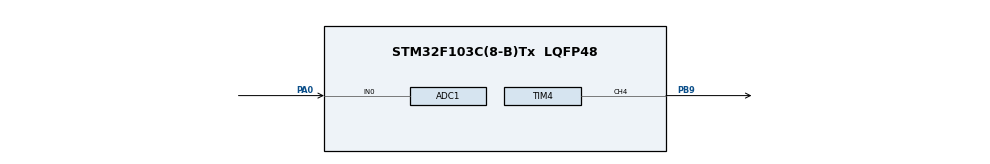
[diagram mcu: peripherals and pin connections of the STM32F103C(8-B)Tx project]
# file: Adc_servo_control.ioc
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ADC1.Channel-0\#ChannelRegularConversion=ADC_CHANNEL_0
ADC1.NbrOfConversionFlag=1
ADC1.Rank-0\#ChannelRegularConversion=1
ADC1.SamplingTime-0\#ChannelRegularConversion=ADC_SAMPLETIME_1CYCLE_5
ADC1.master=1
Dma.ADC1.0.Direction=DMA_PERIPH_TO_MEMORY
Dma.ADC1.0.Instance=DMA1_Channel1
Dma.ADC1.0.MemDataAlignment=DMA_MDATAALIGN_HALFWORD
Dma.ADC1.0.MemInc=DMA_MINC_ENABLE
Dma.ADC1.0.Mode=DMA_CIRCULAR
Dma.ADC1.0.PeriphDataAlignment=DMA_PDATAALIGN_HALFWORD
Dma.ADC1.0.PeriphInc=DMA_PINC_DISABLE
Dma.ADC1.0.Priority=DMA_PRIORITY_HIGH
Dma.Request0=ADC1
Mcu.Family=STM32F1
Mcu.Name=STM32F103C(8-B)Tx
Mcu.Package=LQFP48
NVIC.ADC1_2_IRQn=true\:0\:0\:false\:false\:true\:true\:true\:true
NVIC.DMA1_Channel1_IRQn=true\:0\:0\:false\:false\:true\:false\:true\:true
NVIC.PriorityGroup=NVIC_PRIORITYGROUP_4
NVIC.TIM4_IRQn=true\:0\:0\:false\:false\:true\:true\:true\:true
PA0-WKUP.Signal=ADCx_IN0
PB9.Signal=S_TIM4_CH4
PD0-OSC_IN.Mode=HSE-External-Oscillator
PD0-OSC_IN.Signal=RCC_OSC_IN
PD1-OSC_OUT.Mode=HSE-External-Oscillator
PD1-OSC_OUT.Signal=RCC_OSC_OUT
ProjectManager.HeapSize=0x200
ProjectManager.StackSize=0x400
ProjectManager.TargetToolchain=STM32CubeIDE
RCC.APB1Freq_Value=8000000
RCC.APB2Freq_Value=8000000
SH.ADCx_IN0.0=ADC1_IN0,IN0
SH.S_TIM4_CH4.0=TIM4_CH4,PWM Generation4 CH4
TIM4.Channel-PWM\ Generation4\ CH4=TIM_CHANNEL_4
TIM4.Period=19999
TIM4.Prescaler=71
VP_SYS_VS_ND.Mode=No_Debug
VP_TIM4_VS_ClockSourceINT.Mode=Internal
board=custom

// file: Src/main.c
/* USER CODE END Header */

#include "main.h"

ADC_HandleTypeDef hadc1;
DMA_HandleTypeDef hdma_adc1;
TIM_HandleTypeDef htim4;

/* USER CODE BEGIN PV */
volatile uint16_t pot_v = 0;
/* USER CODE END PV */

void SystemClock_Config(void);
static void MX_GPIO_Init(void);
static void MX_DMA_Init(void);
static void MX_ADC1_Init(void);
static void MX_TIM4_Init(void);

int main(void)
{
    HAL_Init();
    SystemClock_Config();

    MX_GPIO_Init();
    MX_DMA_Init();
    MX_ADC1_Init();
    MX_TIM4_Init();

    /* USER CODE BEGIN 2 */
    HAL_ADCEx_Calibration_Start(&hadc1);
    HAL_ADC_Start_DMA(&hadc1, (uint32_t*)&pot_v, 1);
    HAL_TIM_PWM_Start(&htim4, TIM_CHANNEL_4);
    /* USER CODE END 2 */

    while (1)
    {
        /* USER CODE BEGIN 3 */

        uint32_t pulse = 500 + ((uint32_t)pot_v * 2000 / 4095);
        __HAL_TIM_SET_COMPARE(&htim4, TIM_CHANNEL_4, pulse);

    }
}

/**
  * @retval None
  */
void SystemClock_Config(void)
{
    RCC_OscInitTypeDef RCC_OscInitStruct = {0};
    RCC_ClkInitTypeDef RCC_ClkInitStruct = {0};
    RCC_PeriphCLKInitTypeDef PeriphClkInit = {0};

    RCC_OscInitStruct.OscillatorType = RCC_OSCILLATORTYPE_HSE;
    RCC_OscInitStruct.HSEState = RCC_HSE_ON;
    RCC_OscInitStruct.HSEPredivValue = RCC_HSE_PREDIV_DIV1;
    RCC_OscInitStruct.HSIState = RCC_HSI_ON;
    RCC_OscInitStruct.PLL.PLLState = RCC_PLL_ON;
    RCC_OscInitStruct.PLL.PLLSource = RCC_PLLSOURCE_HSE;
    RCC_OscInitStruct.PLL.PLLMUL = RCC_PLL_MUL9;       // 8MHz x9 = 72MHz
    if (HAL_RCC_OscConfig(&RCC_OscInitStruct) != HAL_OK)
    {
        Error_Handler();
    }

    RCC_ClkInitStruct.ClockType = RCC_CLOCKTYPE_HCLK | RCC_CLOCKTYPE_SYSCLK
                                | RCC_CLOCKTYPE_PCLK1 | RCC_CLOCKTYPE_PCLK2;
    RCC_ClkInitStruct.SYSCLKSource = RCC_SYSCLKSOURCE_PLLCLK;
    RCC_ClkInitStruct.AHBCLKDivider = RCC_SYSCLK_DIV1;
    RCC_ClkInitStruct.APB1CLKDivider = RCC_HCLK_DIV2;
    RCC_ClkInitStruct.APB2CLKDivider = RCC_HCLK_DIV1;
    if (HAL_RCC_ClockConfig(&RCC_ClkInitStruct, FLASH_LATENCY_2) != HAL_OK)
    {
        Error_Handler();
    }

    PeriphClkInit.PeriphClockSelection = RCC_PERIPHCLK_ADC;
    PeriphClkInit.AdcClockSelection = RCC_ADCPCLK2_DIV6;
    if (HAL_RCCEx_PeriphCLKConfig(&PeriphClkInit) != HAL_OK)
    {
        Error_Handler();
    }

}

/**
  * @brief ADC1 Initialization
  * @retval None
  */
static void MX_ADC1_Init(void)
{
    ADC_ChannelConfTypeDef sConfig = {0};

    hadc1.Instance = ADC1;
    hadc1.Init.ScanConvMode = ADC_SCAN_DISABLE;
    hadc1.Init.ContinuousConvMode = ENABLE;
    hadc1.Init.DiscontinuousConvMode = DISABLE;
    hadc1.Init.ExternalTrigConv = ADC_SOFTWARE_START;
    hadc1.Init.DataAlign = ADC_DATAALIGN_RIGHT;
    hadc1.Init.NbrOfConversion = 1;
    if (HAL_ADC_Init(&hadc1) != HAL_OK)
    {
        Error_Handler();
    }

    sConfig.Channel = ADC_CHANNEL_0;
    sConfig.Rank = ADC_REGULAR_RANK_1;
    sConfig.SamplingTime = ADC_SAMPLETIME_55CYCLES_5;
    if (HAL_ADC_ConfigChannel(&hadc1, &sConfig) != HAL_OK)
    {
        Error_Handler();
    }
}

/**
  * @brief TIM4 PWM Initialization

  * @retval None
  */
static void MX_TIM4_Init(void)
{
    TIM_ClockConfigTypeDef sClockSourceConfig = {0};
    TIM_MasterConfigTypeDef sMasterConfig = {0};
    TIM_OC_InitTypeDef sConfigOC = {0};

    htim4.Instance = TIM4;
    htim4.Init.Prescaler = 71;
    htim4.Init.CounterMode = TIM_COUNTERMODE_UP;
    htim4.Init.Period = 19999;
    htim4.Init.ClockDivision = TIM_CLOCKDIVISION_DIV1;
    htim4.Init.AutoReloadPreload = TIM_AUTORELOAD_PRELOAD_DISABLE;
    if (HAL_TIM_Base_Init(&htim4) != HAL_OK)
    {
        Error_Handler();
    }

    sClockSourceConfig.ClockSource = TIM_CLOCKSOURCE_INTERNAL;
    if (HAL_TIM_ConfigClockSource(&htim4, &sClockSourceConfig) != HAL_OK)
    {
        Error_Handler();
    }

    if (HAL_TIM_PWM_Init(&htim4) != HAL_OK)
    {
        Error_Handler();
    }

    sMasterConfig.MasterOutputTrigger = TIM_TRGO_RESET;
    sMasterConfig.MasterSlaveMode = TIM_MASTERSLAVEMODE_DISABLE;
    if (HAL_TIMEx_MasterConfigSynchronization(&htim4, &sMasterConfig) != HAL_OK)
    {
        Error_Handler();
    }

    sConfigOC.OCMode = TIM_OCMODE_PWM1;
    sConfigOC.Pulse = 1500;
    sConfigOC.OCPolarity = TIM_OCPOLARITY_HIGH;
    sConfigOC.OCFastMode = TIM_OCFAST_DISABLE;
    if (HAL_TIM_PWM_ConfigChannel(&htim4, &sConfigOC, TIM_CHANNEL_4) != HAL_OK)
    {
        Error_Handler();
    }

    HAL_TIM_MspPostInit(&htim4);
}

/**
  * @brief DMA Initialization
  * @retval None
  */
static void MX_DMA_Init(void)
{
    __HAL_RCC_DMA1_CLK_ENABLE();

    hdma_adc1.Instance = DMA1_Channel1;
    hdma_adc1.Init.Direction = DMA_PERIPH_TO_MEMORY;
    hdma_adc1.Init.PeriphInc = DMA_PINC_DISABLE;
    hdma_adc1.Init.MemInc = DMA_MINC_DISABLE;
    hdma_adc1.Init.PeriphDataAlignment = DMA_PDATAALIGN_HALFWORD;
    hdma_adc1.Init.MemDataAlignment = DMA_MDATAALIGN_HALFWORD;
    hdma_adc1.Init.Mode = DMA_CIRCULAR;
    hdma_adc1.Init.Priority = DMA_PRIORITY_HIGH;
    if (HAL_DMA_Init(&hdma_adc1) != HAL_OK)
    {
        Error_Handler();
    }

    __HAL_LINKDMA(&hadc1, DMA_Handle, hdma_adc1);

    HAL_NVIC_SetPriority(DMA1_Channel1_IRQn, 0, 0);
    HAL_NVIC_EnableIRQ(DMA1_Channel1_IRQn);
}

/**
  * @brief GPIO Initialization
  * @retval None
  */
static void MX_GPIO_Init(void)
{
    __HAL_RCC_GPIOD_CLK_ENABLE();
    __HAL_RCC_GPIOA_CLK_ENABLE();
    __HAL_RCC_GPIOB_CLK_ENABLE();
}

/**
  * @brief Error Handler
  * @retval None
  */
void Error_Handler(void)
{
    __disable_irq();
    while (1) {}
}
